VERSION 5.8 ;
BUSBITCHARS "[]" ;
DIVIDERCHAR "/" ;

VIA M1M2_C_0
  VIARULE M1M2_C ;
  CUTSIZE 0.15 0.15 ;
  LAYERS met1 via met2 ;
  CUTSPACING 0.17 0.17 ;
  ENCLOSURE 0.085 0.085 0.085 0.085 ;
  ROWCOL 1 1 ;
END M1M2_C_0

VIA M1M2_C_1
  VIARULE M1M2_C ;
  CUTSIZE 0.15 0.15 ;
  LAYERS met1 via met2 ;
  CUTSPACING 0.17 0.17 ;
  ENCLOSURE 0.085 0.085 0.085 0.085 ;
  ROWCOL 2 4 ;
END M1M2_C_1

VIA M1M2_C_2
  VIARULE M1M2_C ;
  CUTSIZE 0.15 0.15 ;
  LAYERS met1 via met2 ;
  CUTSPACING 0.17 0.17 ;
  ENCLOSURE 0.085 0.085 0.085 0.085 ;
  ROWCOL 6 6 ;
END M1M2_C_2

VIA M1M2_C_3
  VIARULE M1M2_C ;
  CUTSIZE 0.15 0.15 ;
  LAYERS met1 via met2 ;
  CUTSPACING 0.17 0.17 ;
  ENCLOSURE 0.085 0.085 0.085 0.085 ;
  ROWCOL 3 6 ;
END M1M2_C_3

VIA M1M2_C_4
  VIARULE M1M2_C ;
  CUTSIZE 0.15 0.15 ;
  LAYERS met1 via met2 ;
  CUTSPACING 0.17 0.17 ;
  ENCLOSURE 0.085 0.085 0.085 0.085 ;
  ROWCOL 1 10 ;
END M1M2_C_4

VIA M1M2_C_5
  VIARULE M1M2_C ;
  CUTSIZE 0.15 0.15 ;
  LAYERS met1 via met2 ;
  CUTSPACING 0.17 0.17 ;
  ENCLOSURE 0.085 0.085 0.085 0.085 ;
  ROWCOL 1 8 ;
END M1M2_C_5

VIA M1M2_C_6
  VIARULE M1M2_C ;
  CUTSIZE 0.15 0.15 ;
  LAYERS met1 via met2 ;
  CUTSPACING 0.17 0.17 ;
  ENCLOSURE 0.085 0.085 0.085 0.085 ;
  ROWCOL 3 8 ;
END M1M2_C_6

VIA M1M2_C_7
  VIARULE M1M2_C ;
  CUTSIZE 0.15 0.15 ;
  LAYERS met1 via met2 ;
  CUTSPACING 0.17 0.17 ;
  ENCLOSURE 0.085 0.085 0.085 0.085 ;
  ROWCOL 6 1 ;
END M1M2_C_7

VIA M1M2_C_8
  VIARULE M1M2_C ;
  CUTSIZE 0.15 0.15 ;
  LAYERS met1 via met2 ;
  CUTSPACING 0.17 0.17 ;
  ENCLOSURE 0.085 0.085 0.085 0.085 ;
  ROWCOL 1 6 ;
END M1M2_C_8

VIA M1M2_C_9
  VIARULE M1M2_C ;
  CUTSIZE 0.15 0.15 ;
  LAYERS met1 via met2 ;
  CUTSPACING 0.17 0.17 ;
  ENCLOSURE 0.085 0.085 0.085 0.085 ;
  ROWCOL 6 3 ;
END M1M2_C_9

VIA M1M2_C_10
  VIARULE M1M2_C ;
  CUTSIZE 0.15 0.15 ;
  LAYERS met1 via met2 ;
  CUTSPACING 0.17 0.17 ;
  ENCLOSURE 0.085 0.085 0.085 0.085 ;
  ROWCOL 1 4 ;
END M1M2_C_10

VIA M1M2_C_11
  VIARULE M1M2_C ;
  CUTSIZE 0.15 0.15 ;
  LAYERS met1 via met2 ;
  CUTSPACING 0.17 0.17 ;
  ENCLOSURE 0.085 0.085 0.085 0.085 ;
  ROWCOL 2 6 ;
END M1M2_C_11

VIA M1M2_C_12
  VIARULE M1M2_C ;
  CUTSIZE 0.15 0.15 ;
  LAYERS met1 via met2 ;
  CUTSPACING 0.17 0.17 ;
  ENCLOSURE 0.085 0.085 0.085 0.085 ;
  ROWCOL 3 3 ;
END M1M2_C_12

VIA M1M2_C_13
  VIARULE M1M2_C ;
  CUTSIZE 0.15 0.15 ;
  LAYERS met1 via met2 ;
  CUTSPACING 0.17 0.17 ;
  ENCLOSURE 0.085 0.085 0.085 0.085 ;
  ROWCOL 2 3 ;
END M1M2_C_13

VIA M1M2_C_14
  VIARULE M1M2_C ;
  CUTSIZE 0.15 0.15 ;
  LAYERS met1 via met2 ;
  CUTSPACING 0.17 0.17 ;
  ENCLOSURE 0.085 0.085 0.085 0.085 ;
  ROWCOL 3 1 ;
END M1M2_C_14

VIA M1M2_C_15
  VIARULE M1M2_C ;
  CUTSIZE 0.15 0.15 ;
  LAYERS met1 via met2 ;
  CUTSPACING 0.17 0.17 ;
  ENCLOSURE 0.085 0.085 0.085 0.085 ;
  ROWCOL 4 1 ;
END M1M2_C_15

VIA M1M2_C_16
  VIARULE M1M2_C ;
  CUTSIZE 0.15 0.15 ;
  LAYERS met1 via met2 ;
  CUTSPACING 0.17 0.17 ;
  ENCLOSURE 0.085 0.085 0.085 0.085 ;
  ROWCOL 2 1 ;
END M1M2_C_16

VIA M1M2_C_17
  VIARULE M1M2_C ;
  CUTSIZE 0.15 0.15 ;
  LAYERS met1 via met2 ;
  CUTSPACING 0.17 0.17 ;
  ENCLOSURE 0.085 0.085 0.085 0.085 ;
  ROWCOL 1 2 ;
END M1M2_C_17

VIA M1M2_C_18
  VIARULE M1M2_C ;
  CUTSIZE 0.15 0.15 ;
  LAYERS met1 via met2 ;
  CUTSPACING 0.17 0.17 ;
  ENCLOSURE 0.085 0.085 0.085 0.085 ;
  ROWCOL 2 2 ;
END M1M2_C_18

VIA M1M2_C_19
  VIARULE M1M2_C ;
  CUTSIZE 0.15 0.15 ;
  LAYERS met1 via met2 ;
  CUTSPACING 0.17 0.17 ;
  ENCLOSURE 0.085 0.085 0.085 0.085 ;
  ROWCOL 6 2 ;
END M1M2_C_19

VIA M1M2_C_20
  VIARULE M1M2_C ;
  CUTSIZE 0.15 0.15 ;
  LAYERS met1 via met2 ;
  CUTSPACING 0.17 0.17 ;
  ENCLOSURE 0.085 0.085 0.085 0.085 ;
  ROWCOL 4 2 ;
END M1M2_C_20

VIA M1M2_C_21
  VIARULE M1M2_C ;
  CUTSIZE 0.15 0.15 ;
  LAYERS met1 via met2 ;
  CUTSPACING 0.17 0.17 ;
  ENCLOSURE 0.085 0.085 0.085 0.085 ;
  ROWCOL 3 2 ;
END M1M2_C_21

VIA L1M1_C_22
  VIARULE L1M1_C ;
  CUTSIZE 0.17 0.17 ;
  LAYERS li1 mcon met1 ;
  CUTSPACING 0.19 0.19 ;
  ENCLOSURE 0 0 0.06 0.06 ;
  ROWCOL 1 1 ;
END L1M1_C_22

VIA L1M1_C_23
  VIARULE L1M1_C ;
  CUTSIZE 0.17 0.17 ;
  LAYERS li1 mcon met1 ;
  CUTSPACING 0.19 0.19 ;
  ENCLOSURE 0 0 0.06 0.06 ;
  ROWCOL 2 4 ;
END L1M1_C_23

VIA L1M1_C_24
  VIARULE L1M1_C ;
  CUTSIZE 0.17 0.17 ;
  LAYERS li1 mcon met1 ;
  CUTSPACING 0.19 0.19 ;
  ENCLOSURE 0 0 0.06 0.06 ;
  ROWCOL 1 2 ;
END L1M1_C_24

VIA L1M1_C_25
  VIARULE L1M1_C ;
  CUTSIZE 0.17 0.17 ;
  LAYERS li1 mcon met1 ;
  CUTSPACING 0.19 0.19 ;
  ENCLOSURE 0 0 0.06 0.06 ;
  ROWCOL 3 6 ;
END L1M1_C_25

VIA L1M1_C_26
  VIARULE L1M1_C ;
  CUTSIZE 0.17 0.17 ;
  LAYERS li1 mcon met1 ;
  CUTSPACING 0.19 0.19 ;
  ENCLOSURE 0 0 0.06 0.06 ;
  ROWCOL 1 3 ;
END L1M1_C_26

VIA L1M1_C_27
  VIARULE L1M1_C ;
  CUTSIZE 0.17 0.17 ;
  LAYERS li1 mcon met1 ;
  CUTSPACING 0.19 0.19 ;
  ENCLOSURE 0 0 0.06 0.06 ;
  ROWCOL 2 8 ;
END L1M1_C_27

VIA L1M1_C_28
  VIARULE L1M1_C ;
  CUTSIZE 0.17 0.17 ;
  LAYERS li1 mcon met1 ;
  CUTSPACING 0.19 0.19 ;
  ENCLOSURE 0 0 0.06 0.06 ;
  ROWCOL 5 2 ;
END L1M1_C_28

VIA L1M1_C_29
  VIARULE L1M1_C ;
  CUTSIZE 0.17 0.17 ;
  LAYERS li1 mcon met1 ;
  CUTSPACING 0.19 0.19 ;
  ENCLOSURE 0 0 0.06 0.06 ;
  ROWCOL 2 1 ;
END L1M1_C_29

VIA L1M1_C_30
  VIARULE L1M1_C ;
  CUTSIZE 0.17 0.17 ;
  LAYERS li1 mcon met1 ;
  CUTSPACING 0.19 0.19 ;
  ENCLOSURE 0 0 0.06 0.06 ;
  ROWCOL 2 2 ;
END L1M1_C_30

VIA L1M1_C_31
  VIARULE L1M1_C ;
  CUTSIZE 0.17 0.17 ;
  LAYERS li1 mcon met1 ;
  CUTSPACING 0.19 0.19 ;
  ENCLOSURE 0 0 0.06 0.06 ;
  ROWCOL 2 6 ;
END L1M1_C_31

VIA L1M1_C_32
  VIARULE L1M1_C ;
  CUTSIZE 0.17 0.17 ;
  LAYERS li1 mcon met1 ;
  CUTSPACING 0.19 0.19 ;
  ENCLOSURE 0 0 0.06 0.06 ;
  ROWCOL 2 3 ;
END L1M1_C_32

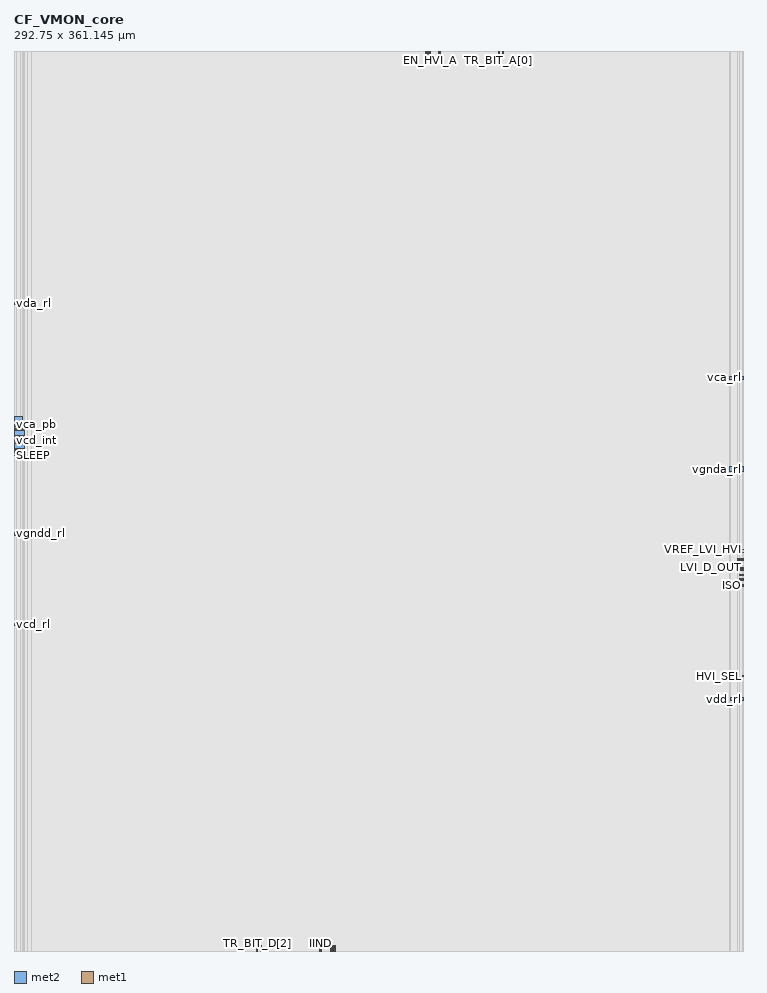
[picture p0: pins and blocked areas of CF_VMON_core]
MACRO CF_VMON_core
  ORIGIN 0 0 ;
  FOREIGN CF_VMON_core 0 0 ;
  SIZE 292.75 BY 361.145 ;
  PIN vgndd_rl
    DIRECTION INOUT ;
    USE SIGNAL ;
    PORT
      LAYER met2 ;
        RECT 0 166.54 6.875 168.46 ;
    END
  END vgndd_rl
  PIN vgndd_nb
    DIRECTION INOUT ;
    USE SIGNAL ;
    PORT
      LAYER met2 ;
        RECT 0 205.94 3.635 206.44 ;
    END
  END vgndd_nb
  PIN vgndd
    DIRECTION INOUT ;
    USE SIGNAL ;
    PORT
      LAYER met2 ;
        RECT 0 203.8 4.265 205.8 ;
    END
  END vgndd
  PIN vgnda_rl
    DIRECTION INOUT ;
    USE SIGNAL ;
    PORT
      LAYER met2 ;
        RECT 287.015 192.43 292.75 194.35 ;
    END
  END vgnda_rl
  PIN vgnda_nb
    DIRECTION INOUT ;
    USE SIGNAL ;
    PORT
      LAYER met2 ;
        RECT 0 208.86 4.105 209.36 ;
    END
  END vgnda_nb
  PIN vgnda
    DIRECTION INOUT ;
    USE SIGNAL ;
    PORT
      LAYER met2 ;
        RECT 0 206.72 4.1 208.72 ;
    END
  END vgnda
  PIN vdd_rl
    DIRECTION INOUT ;
    USE SIGNAL ;
    PORT
      LAYER met2 ;
        RECT 287.455 100.665 292.66 101.565 ;
    END
  END vdd_rl
  PIN vda_rl
    DIRECTION INOUT ;
    USE SIGNAL ;
    PORT
      LAYER met2 ;
        RECT 0.2 259.325 5.39 260.225 ;
    END
  END vda_rl
  PIN vcd_rl
    DIRECTION INOUT ;
    USE SIGNAL ;
    PORT
      LAYER met2 ;
        RECT 0 130.43 4.04 131.43 ;
    END
  END vcd_rl
  PIN vcd_pb
    DIRECTION INOUT ;
    USE SIGNAL ;
    PORT
      LAYER met2 ;
        RECT 0 200.88 2.475 201.38 ;
    END
  END vcd_pb
  PIN vcd
    DIRECTION INOUT ;
    USE SIGNAL ;
    PORT
      LAYER met2 ;
        RECT 0 199.435 2.475 200.395 ;
    END
  END vcd
  PIN vca_rl
    DIRECTION INOUT ;
    USE SIGNAL ;
    PORT
      LAYER met2 ;
        RECT 287.31 229.46 292.75 230.46 ;
    END
  END vca_rl
  PIN vca_pb
    DIRECTION INOUT ;
    USE SIGNAL ;
    PORT
      LAYER met2 ;
        RECT 0 210.915 3.475 211.415 ;
    END
  END vca_pb
  PIN vca
    DIRECTION INOUT ;
    USE SIGNAL ;
    PORT
      LAYER met2 ;
        RECT 0 212.51 3.245 214.43 ;
    END
  END vca
  PIN PRES_D_OUT
    DIRECTION OUTPUT ;
    USE SIGNAL ;
    PORT
      LAYER met2 ;
        RECT 290.335 156.55 292.75 156.79 ;
    END
  END PRES_D_OUT
  PIN PRES_A_OUT
    DIRECTION OUTPUT ;
    USE SIGNAL ;
    PORT
      LAYER met2 ;
        RECT 290.4 153.595 292.75 153.835 ;
    END
  END PRES_A_OUT
  PIN LVI_D_OUT
    DIRECTION OUTPUT ;
    USE SIGNAL ;
    PORT
      LAYER met2 ;
        RECT 291.09 150.64 292.75 150.88 ;
    END
  END LVI_D_OUT
  PIN LVI_A_OUT
    DIRECTION OUTPUT ;
    USE SIGNAL ;
    PORT
      LAYER met2 ;
        RECT 291.055 148.7 292.75 148.94 ;
    END
  END LVI_A_OUT
  PIN HVI_OUT
    DIRECTION OUTPUT ;
    USE SIGNAL ;
    PORT
      LAYER met2 ;
        RECT 291.055 149.16 292.75 149.4 ;
    END
  END HVI_OUT
  PIN TR_BIT_D[3]
    DIRECTION INPUT ;
    USE SIGNAL ;
    PORT
      LAYER met1 ;
        RECT 97.115 0 97.255 2.15 ;
    END
  END TR_BIT_D[3]
  PIN TR_BIT_D[2]
    DIRECTION INPUT ;
    USE SIGNAL ;
    PORT
      LAYER met1 ;
        RECT 97.555 0 97.695 2.15 ;
    END
  END TR_BIT_D[2]
  PIN TR_BIT_D[1]
    DIRECTION INPUT ;
    USE SIGNAL ;
    PORT
      LAYER met1 ;
        RECT 98.875 0 99.015 2.15 ;
    END
  END TR_BIT_D[1]
  PIN TR_BIT_D[0]
    DIRECTION INPUT ;
    USE SIGNAL ;
    PORT
      LAYER met1 ;
        RECT 99.315 0 99.455 2.15 ;
    END
  END TR_BIT_D[0]
  PIN TR_BIT_A[3]
    DIRECTION INPUT ;
    USE SIGNAL ;
    PORT
      LAYER met1 ;
        RECT 196.44 358.995 196.58 361.145 ;
    END
  END TR_BIT_A[3]
  PIN TR_BIT_A[2]
    DIRECTION INPUT ;
    USE SIGNAL ;
    PORT
      LAYER met1 ;
        RECT 196 358.995 196.14 361.145 ;
    END
  END TR_BIT_A[2]
  PIN TR_BIT_A[1]
    DIRECTION INPUT ;
    USE SIGNAL ;
    PORT
      LAYER met1 ;
        RECT 194.68 358.995 194.82 361.145 ;
    END
  END TR_BIT_A[1]
  PIN TR_BIT_A[0]
    DIRECTION INPUT ;
    USE SIGNAL ;
    PORT
      LAYER met1 ;
        RECT 194.24 358.995 194.38 361.145 ;
    END
  END TR_BIT_A[0]
  PIN PD
    DIRECTION INPUT ;
    USE SIGNAL ;
    PORT
      LAYER met2 ;
        RECT 292.25 146.265 292.75 146.465 ;
    END
  END PD
  PIN LVI_D_SEL[3]
    DIRECTION INPUT ;
    USE SIGNAL ;
    PORT
      LAYER met1 ;
        RECT 128.375 0 128.575 2.15 ;
    END
  END LVI_D_SEL[3]
  PIN LVI_D_SEL[2]
    DIRECTION INPUT ;
    USE SIGNAL ;
    PORT
      LAYER met1 ;
        RECT 127.945 0 128.145 2.15 ;
    END
  END LVI_D_SEL[2]
  PIN LVI_D_SEL[1]
    DIRECTION INPUT ;
    USE SIGNAL ;
    PORT
      LAYER met1 ;
        RECT 127.515 0 127.715 2.15 ;
    END
  END LVI_D_SEL[1]
  PIN LVI_D_SEL[0]
    DIRECTION INPUT ;
    USE SIGNAL ;
    PORT
      LAYER met1 ;
        RECT 127.085 0 127.285 2.15 ;
    END
  END LVI_D_SEL[0]
  PIN LVI_A_SEL[3]
    DIRECTION INPUT ;
    USE SIGNAL ;
    PORT
      LAYER met1 ;
        RECT 165.12 358.995 165.32 361.145 ;
    END
  END LVI_A_SEL[3]
  PIN LVI_A_SEL[2]
    DIRECTION INPUT ;
    USE SIGNAL ;
    PORT
      LAYER met1 ;
        RECT 165.55 358.995 165.75 361.145 ;
    END
  END LVI_A_SEL[2]
  PIN LVI_A_SEL[1]
    DIRECTION INPUT ;
    USE SIGNAL ;
    PORT
      LAYER met1 ;
        RECT 165.98 358.995 166.18 361.145 ;
    END
  END LVI_A_SEL[1]
  PIN ISO
    DIRECTION INPUT ;
    USE SIGNAL ;
    PORT
      LAYER met2 ;
        RECT 292.26 146.695 292.75 146.895 ;
    END
  END ISO
  PIN vca_int
    DIRECTION INOUT ;
    USE SIGNAL ;
    PORT
      LAYER met2 ;
        RECT 0 209.64 4.115 210.635 ;
    END
  END vca_int
  PIN vcd_int
    DIRECTION INOUT ;
    USE SIGNAL ;
    PORT
      LAYER met2 ;
        RECT 0 201.75 4.28 203.5 ;
    END
  END vcd_int
  PIN VREF_PRES
    DIRECTION INPUT ;
    USE SIGNAL ;
    PORT
      LAYER met1 ;
        RECT 291.19 159.73 292.75 159.93 ;
    END
  END VREF_PRES
  PIN VREF_LVI_HVI
    DIRECTION INPUT ;
    USE SIGNAL ;
    PORT
      LAYER met1 ;
        RECT 291.405 160.93 292.75 161.13 ;
    END
  END VREF_LVI_HVI
  PIN SLEEP
    DIRECTION INPUT ;
    USE SIGNAL ;
    PORT
      LAYER met2 ;
        RECT 0 198.745 1.13 199.005 ;
    END
  END SLEEP
  PIN en_iso_vcca
    DIRECTION INPUT ;
    USE SIGNAL ;
    PORT
      LAYER met2 ;
        RECT 290.98 152.855 292.75 153.095 ;
    END
  END en_iso_vcca
  PIN HVI_SEL
    DIRECTION INPUT ;
    USE SIGNAL ;
    PORT
      LAYER met2 ;
        RECT 292.375 110.215 292.75 110.415 ;
    END
  END HVI_SEL
  PIN EN_HVI_A
    DIRECTION INPUT ;
    USE SIGNAL ;
    PORT
      LAYER met1 ;
        RECT 166.955 359 167.155 361.145 ;
    END
  END EN_HVI_A
  PIN EN_LVI_A
    DIRECTION INPUT ;
    USE SIGNAL ;
    PORT
      LAYER met2 ;
        RECT 290.335 157.24 292.75 157.44 ;
    END
  END EN_LVI_A
  PIN EN_LVI_D
    DIRECTION INPUT ;
    USE SIGNAL ;
    PORT
      LAYER met1 ;
        RECT 128.805 0 129.005 2.15 ;
    END
  END EN_LVI_D
  PIN EN_PRES_A
    DIRECTION INPUT ;
    USE SIGNAL ;
    PORT
      LAYER met1 ;
        RECT 170.995 358.995 171.195 361.145 ;
    END
  END EN_PRES_A
  PIN EN_PRES_D
    DIRECTION INPUT ;
    USE SIGNAL ;
    PORT
      LAYER met1 ;
        RECT 122.5 0 122.7 2.15 ;
    END
  END EN_PRES_D
  PIN IINA
    DIRECTION INPUT ;
    USE SIGNAL ;
    PORT
      LAYER met1 ;
        RECT 170.46 359.13 170.76 361.145 ;
    END
  END IINA
  PIN IIND
    DIRECTION INPUT ;
    USE SIGNAL ;
    PORT
      LAYER met1 ;
        RECT 122.935 0 123.235 1.24 ;
    END
  END IIND
  PIN LVI_A_SEL[0]
    DIRECTION INPUT ;
    USE SIGNAL ;
    PORT
      LAYER met1 ;
        RECT 166.41 358.995 166.61 361.145 ;
    END
  END LVI_A_SEL[0]
  OBS
    LAYER li1 ;
      RECT 0 0 292.75 361.145 ;
    LAYER met1 ;
      RECT 0 0 97.115 361.145 ;
      RECT 97.115 2.15 97.255 361.145 ;
      RECT 97.255 0 97.555 361.145 ;
      RECT 97.555 2.15 97.695 361.145 ;
      RECT 97.695 0 98.875 361.145 ;
      RECT 98.875 2.15 99.015 361.145 ;
      RECT 99.015 0 99.315 361.145 ;
      RECT 99.315 2.15 99.455 361.145 ;
      RECT 99.455 0 122.5 361.145 ;
      RECT 122.5 2.15 122.7 361.145 ;
      RECT 122.7 0 122.935 361.145 ;
      RECT 122.935 1.24 123.235 361.145 ;
      RECT 123.235 0 127.085 361.145 ;
      RECT 127.085 2.15 127.285 361.145 ;
      RECT 127.285 0 127.515 361.145 ;
      RECT 127.515 2.15 127.715 361.145 ;
      RECT 127.715 0 127.945 361.145 ;
      RECT 127.945 2.15 128.145 361.145 ;
      RECT 128.145 0 128.375 361.145 ;
      RECT 128.375 2.15 128.575 361.145 ;
      RECT 128.575 0 128.805 361.145 ;
      RECT 128.805 2.15 129.005 361.145 ;
      RECT 129.005 0 165.12 361.145 ;
      RECT 165.12 0 165.32 358.995 ;
      RECT 165.32 0 165.55 361.145 ;
      RECT 165.55 0 165.75 358.995 ;
      RECT 165.75 0 165.98 361.145 ;
      RECT 165.98 0 166.18 358.995 ;
      RECT 166.18 0 166.41 361.145 ;
      RECT 166.41 0 166.61 358.995 ;
      RECT 166.61 0 166.955 361.145 ;
      RECT 166.955 0 167.155 359 ;
      RECT 167.155 0 170.46 361.145 ;
      RECT 170.46 0 170.76 359.13 ;
      RECT 170.76 0 170.995 361.145 ;
      RECT 170.995 0 171.195 358.995 ;
      RECT 171.195 0 194.24 361.145 ;
      RECT 194.24 0 194.38 358.995 ;
      RECT 194.38 0 194.68 361.145 ;
      RECT 194.68 0 194.82 358.995 ;
      RECT 194.82 0 196 361.145 ;
      RECT 196 0 196.14 358.995 ;
      RECT 196.14 0 196.44 361.145 ;
      RECT 196.44 0 196.58 358.995 ;
      RECT 196.58 0 291.19 361.145 ;
      RECT 291.19 0 291.405 159.73 ;
      RECT 291.19 159.93 291.405 361.145 ;
      RECT 291.405 0 292.75 159.73 ;
      RECT 291.405 159.93 292.75 160.93 ;
      RECT 291.405 161.13 292.75 361.145 ;
    LAYER met2 ;
      RECT 0 0 0.2 130.43 ;
      RECT 0 131.43 0.2 166.54 ;
      RECT 0 168.46 0.2 198.745 ;
      RECT 0 199.005 0.2 199.435 ;
      RECT 0 200.395 0.2 200.88 ;
      RECT 0 201.38 0.2 201.75 ;
      RECT 0 203.5 0.2 203.8 ;
      RECT 0 205.8 0.2 205.94 ;
      RECT 0 206.44 0.2 206.72 ;
      RECT 0 208.72 0.2 208.86 ;
      RECT 0 209.36 0.2 209.64 ;
      RECT 0 210.635 0.2 210.915 ;
      RECT 0 211.415 0.2 212.51 ;
      RECT 0 214.43 0.2 361.145 ;
      RECT 0.2 0 1.13 130.43 ;
      RECT 0.2 131.43 1.13 166.54 ;
      RECT 0.2 168.46 1.13 198.745 ;
      RECT 0.2 199.005 1.13 199.435 ;
      RECT 0.2 200.395 1.13 200.88 ;
      RECT 0.2 201.38 1.13 201.75 ;
      RECT 0.2 203.5 1.13 203.8 ;
      RECT 0.2 205.8 1.13 205.94 ;
      RECT 0.2 206.44 1.13 206.72 ;
      RECT 0.2 208.72 1.13 208.86 ;
      RECT 0.2 209.36 1.13 209.64 ;
      RECT 0.2 210.635 1.13 210.915 ;
      RECT 0.2 211.415 1.13 212.51 ;
      RECT 0.2 214.43 1.13 259.325 ;
      RECT 0.2 260.225 1.13 361.145 ;
      RECT 1.13 0 2.475 130.43 ;
      RECT 1.13 131.43 2.475 166.54 ;
      RECT 1.13 168.46 2.475 199.435 ;
      RECT 1.13 200.395 2.475 200.88 ;
      RECT 1.13 201.38 2.475 201.75 ;
      RECT 1.13 203.5 2.475 203.8 ;
      RECT 1.13 205.8 2.475 205.94 ;
      RECT 1.13 206.44 2.475 206.72 ;
      RECT 1.13 208.72 2.475 208.86 ;
      RECT 1.13 209.36 2.475 209.64 ;
      RECT 1.13 210.635 2.475 210.915 ;
      RECT 1.13 211.415 2.475 212.51 ;
      RECT 1.13 214.43 2.475 259.325 ;
      RECT 1.13 260.225 2.475 361.145 ;
      RECT 2.475 0 3.245 130.43 ;
      RECT 2.475 131.43 3.245 166.54 ;
      RECT 2.475 168.46 3.245 201.75 ;
      RECT 2.475 203.5 3.245 203.8 ;
      RECT 2.475 205.8 3.245 205.94 ;
      RECT 2.475 206.44 3.245 206.72 ;
      RECT 2.475 208.72 3.245 208.86 ;
      RECT 2.475 209.36 3.245 209.64 ;
      RECT 2.475 210.635 3.245 210.915 ;
      RECT 2.475 211.415 3.245 212.51 ;
      RECT 2.475 214.43 3.245 259.325 ;
      RECT 2.475 260.225 3.245 361.145 ;
      RECT 3.245 0 3.475 130.43 ;
      RECT 3.245 131.43 3.475 166.54 ;
      RECT 3.245 168.46 3.475 201.75 ;
      RECT 3.245 203.5 3.475 203.8 ;
      RECT 3.245 205.8 3.475 205.94 ;
      RECT 3.245 206.44 3.475 206.72 ;
      RECT 3.245 208.72 3.475 208.86 ;
      RECT 3.245 209.36 3.475 209.64 ;
      RECT 3.245 210.635 3.475 210.915 ;
      RECT 3.245 211.415 3.475 259.325 ;
      RECT 3.245 260.225 3.475 361.145 ;
      RECT 3.475 0 3.635 130.43 ;
      RECT 3.475 131.43 3.635 166.54 ;
      RECT 3.475 168.46 3.635 201.75 ;
      RECT 3.475 203.5 3.635 203.8 ;
      RECT 3.475 205.8 3.635 205.94 ;
      RECT 3.475 206.44 3.635 206.72 ;
      RECT 3.475 208.72 3.635 208.86 ;
      RECT 3.475 209.36 3.635 209.64 ;
      RECT 3.475 210.635 3.635 259.325 ;
      RECT 3.475 260.225 3.635 361.145 ;
      RECT 3.635 0 4.04 130.43 ;
      RECT 3.635 131.43 4.04 166.54 ;
      RECT 3.635 168.46 4.04 201.75 ;
      RECT 3.635 203.5 4.04 203.8 ;
      RECT 3.635 205.8 4.04 206.72 ;
      RECT 3.635 208.72 4.04 208.86 ;
      RECT 3.635 209.36 4.04 209.64 ;
      RECT 3.635 210.635 4.04 259.325 ;
      RECT 3.635 260.225 4.04 361.145 ;
      RECT 4.04 0 4.1 166.54 ;
      RECT 4.04 168.46 4.1 201.75 ;
      RECT 4.04 203.5 4.1 203.8 ;
      RECT 4.04 205.8 4.1 206.72 ;
      RECT 4.04 208.72 4.1 208.86 ;
      RECT 4.04 209.36 4.1 209.64 ;
      RECT 4.04 210.635 4.1 259.325 ;
      RECT 4.04 260.225 4.1 361.145 ;
      RECT 4.1 0 4.105 166.54 ;
      RECT 4.1 168.46 4.105 201.75 ;
      RECT 4.1 203.5 4.105 203.8 ;
      RECT 4.1 205.8 4.105 208.86 ;
      RECT 4.1 209.36 4.105 209.64 ;
      RECT 4.1 210.635 4.105 259.325 ;
      RECT 4.1 260.225 4.105 361.145 ;
      RECT 4.105 0 4.115 166.54 ;
      RECT 4.105 168.46 4.115 201.75 ;
      RECT 4.105 203.5 4.115 203.8 ;
      RECT 4.105 205.8 4.115 209.64 ;
      RECT 4.105 210.635 4.115 259.325 ;
      RECT 4.105 260.225 4.115 361.145 ;
      RECT 4.115 0 4.265 166.54 ;
      RECT 4.115 168.46 4.265 201.75 ;
      RECT 4.115 203.5 4.265 203.8 ;
      RECT 4.115 205.8 4.265 259.325 ;
      RECT 4.115 260.225 4.265 361.145 ;
      RECT 4.265 0 4.28 166.54 ;
      RECT 4.265 168.46 4.28 201.75 ;
      RECT 4.265 203.5 4.28 259.325 ;
      RECT 4.265 260.225 4.28 361.145 ;
      RECT 4.28 0 5.39 166.54 ;
      RECT 4.28 168.46 5.39 259.325 ;
      RECT 4.28 260.225 5.39 361.145 ;
      RECT 5.39 0 6.875 166.54 ;
      RECT 5.39 168.46 6.875 361.145 ;
      RECT 6.875 0 287.015 361.145 ;
      RECT 287.015 0 287.31 192.43 ;
      RECT 287.015 194.35 287.31 361.145 ;
      RECT 287.31 0 287.455 192.43 ;
      RECT 287.31 194.35 287.455 229.46 ;
      RECT 287.31 230.46 287.455 361.145 ;
      RECT 287.455 0 290.335 100.665 ;
      RECT 287.455 101.565 290.335 192.43 ;
      RECT 287.455 194.35 290.335 229.46 ;
      RECT 287.455 230.46 290.335 361.145 ;
      RECT 290.335 0 290.4 100.665 ;
      RECT 290.335 101.565 290.4 156.55 ;
      RECT 290.335 156.79 290.4 157.24 ;
      RECT 290.335 157.44 290.4 192.43 ;
      RECT 290.335 194.35 290.4 229.46 ;
      RECT 290.335 230.46 290.4 361.145 ;
      RECT 290.4 0 290.98 100.665 ;
      RECT 290.4 101.565 290.98 153.595 ;
      RECT 290.4 153.835 290.98 156.55 ;
      RECT 290.4 156.79 290.98 157.24 ;
      RECT 290.4 157.44 290.98 192.43 ;
      RECT 290.4 194.35 290.98 229.46 ;
      RECT 290.4 230.46 290.98 361.145 ;
      RECT 290.98 0 291.055 100.665 ;
      RECT 290.98 101.565 291.055 152.855 ;
      RECT 290.98 153.095 291.055 153.595 ;
      RECT 290.98 153.835 291.055 156.55 ;
      RECT 290.98 156.79 291.055 157.24 ;
      RECT 290.98 157.44 291.055 192.43 ;
      RECT 290.98 194.35 291.055 229.46 ;
      RECT 290.98 230.46 291.055 361.145 ;
      RECT 291.055 0 291.09 100.665 ;
      RECT 291.055 101.565 291.09 148.7 ;
      RECT 291.055 148.94 291.09 149.16 ;
      RECT 291.055 149.4 291.09 152.855 ;
      RECT 291.055 153.095 291.09 153.595 ;
      RECT 291.055 153.835 291.09 156.55 ;
      RECT 291.055 156.79 291.09 157.24 ;
      RECT 291.055 157.44 291.09 192.43 ;
      RECT 291.055 194.35 291.09 229.46 ;
      RECT 291.055 230.46 291.09 361.145 ;
      RECT 291.09 0 292.25 100.665 ;
      RECT 291.09 101.565 292.25 148.7 ;
      RECT 291.09 148.94 292.25 149.16 ;
      RECT 291.09 149.4 292.25 150.64 ;
      RECT 291.09 150.88 292.25 152.855 ;
      RECT 291.09 153.095 292.25 153.595 ;
      RECT 291.09 153.835 292.25 156.55 ;
      RECT 291.09 156.79 292.25 157.24 ;
      RECT 291.09 157.44 292.25 192.43 ;
      RECT 291.09 194.35 292.25 229.46 ;
      RECT 291.09 230.46 292.25 361.145 ;
      RECT 292.25 0 292.26 100.665 ;
      RECT 292.25 101.565 292.26 146.265 ;
      RECT 292.25 146.465 292.26 148.7 ;
      RECT 292.25 148.94 292.26 149.16 ;
      RECT 292.25 149.4 292.26 150.64 ;
      RECT 292.25 150.88 292.26 152.855 ;
      RECT 292.25 153.095 292.26 153.595 ;
      RECT 292.25 153.835 292.26 156.55 ;
      RECT 292.25 156.79 292.26 157.24 ;
      RECT 292.25 157.44 292.26 192.43 ;
      RECT 292.25 194.35 292.26 229.46 ;
      RECT 292.25 230.46 292.26 361.145 ;
      RECT 292.26 0 292.375 100.665 ;
      RECT 292.26 101.565 292.375 146.265 ;
      RECT 292.26 146.465 292.375 146.695 ;
      RECT 292.26 146.895 292.375 148.7 ;
      RECT 292.26 148.94 292.375 149.16 ;
      RECT 292.26 149.4 292.375 150.64 ;
      RECT 292.26 150.88 292.375 152.855 ;
      RECT 292.26 153.095 292.375 153.595 ;
      RECT 292.26 153.835 292.375 156.55 ;
      RECT 292.26 156.79 292.375 157.24 ;
      RECT 292.26 157.44 292.375 192.43 ;
      RECT 292.26 194.35 292.375 229.46 ;
      RECT 292.26 230.46 292.375 361.145 ;
      RECT 292.375 0 292.66 100.665 ;
      RECT 292.375 101.565 292.66 110.215 ;
      RECT 292.375 110.415 292.66 146.265 ;
      RECT 292.375 146.465 292.66 146.695 ;
      RECT 292.375 146.895 292.66 148.7 ;
      RECT 292.375 148.94 292.66 149.16 ;
      RECT 292.375 149.4 292.66 150.64 ;
      RECT 292.375 150.88 292.66 152.855 ;
      RECT 292.375 153.095 292.66 153.595 ;
      RECT 292.375 153.835 292.66 156.55 ;
      RECT 292.375 156.79 292.66 157.24 ;
      RECT 292.375 157.44 292.66 192.43 ;
      RECT 292.375 194.35 292.66 229.46 ;
      RECT 292.375 230.46 292.66 361.145 ;
      RECT 292.66 0 292.75 110.215 ;
      RECT 292.66 110.415 292.75 146.265 ;
      RECT 292.66 146.465 292.75 146.695 ;
      RECT 292.66 146.895 292.75 148.7 ;
      RECT 292.66 148.94 292.75 149.16 ;
      RECT 292.66 149.4 292.75 150.64 ;
      RECT 292.66 150.88 292.75 152.855 ;
      RECT 292.66 153.095 292.75 153.595 ;
      RECT 292.66 153.835 292.75 156.55 ;
      RECT 292.66 156.79 292.75 157.24 ;
      RECT 292.66 157.44 292.75 192.43 ;
      RECT 292.66 194.35 292.75 229.46 ;
      RECT 292.66 230.46 292.75 361.145 ;
  END
END CF_VMON_core

END LIBRARY
